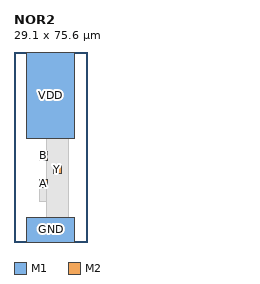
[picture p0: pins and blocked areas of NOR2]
MACRO NOR2
  CLASS CORE ;
  ORIGIN 0 0 ;
  SIZE 29.100 BY 75.600 ;
  SYMMETRY X Y ;
  SITE TR1um_access_site ;
  PIN VDD
    DIRECTION INOUT ;
    USE POWER ;
    PORT
      LAYER M1 ;
        RECT 5.000 41.000 24.100 75.600 ;
    END
  END VDD
  PIN GND
    DIRECTION INOUT ;
    USE GROUND ;
    PORT
      LAYER M1 ;
        RECT 5.000 0.000 24.100 9.800 ;
    END
  END GND
  PIN A
    DIRECTION INPUT ;
    USE SIGNAL ;
    PORT
      LAYER M2 ;
        RECT 10.100 21.600 13.500 25.000 ;
    END
  END A
  PIN B
    DIRECTION INPUT ;
    USE SIGNAL ;
    PORT
      LAYER M2 ;
        RECT 10.100 32.600 13.500 36.000 ;
    END
  END B
  PIN Y
    DIRECTION OUTPUT ;
    USE SIGNAL ;
    PORT
      LAYER M2 ;
        RECT 15.600 27.100 19.000 30.500 ;
    END
  END Y
  OBS
    LAYER M1 ;
      RECT 10.100 16.000 13.500 25.000 ;
    LAYER M1 ;
      RECT 10.100 32.600 18.100 36.000 ;
    LAYER M1 ;
      RECT 13.100 41.000 15.700 51.200 ;
    LAYER M1 ;
      RECT 13.100 6.400 21.500 51.200 ;
    LAYER V1 ;
      RECT 11.100 22.600 12.500 24.000 ;
    LAYER V1 ;
      RECT 16.600 28.100 18.000 29.500 ;
    LAYER V1 ;
      RECT 11.100 33.600 12.500 35.000 ;
  END
END NOR2
